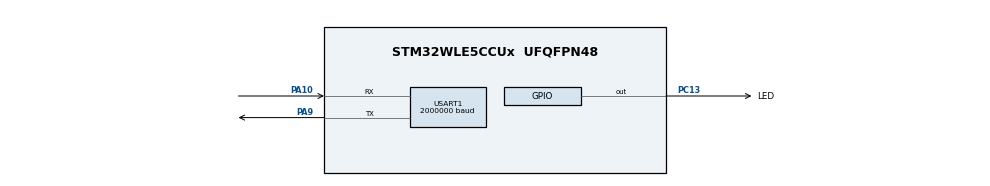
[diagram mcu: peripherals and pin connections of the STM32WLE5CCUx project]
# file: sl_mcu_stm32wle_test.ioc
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Mcu.Family=STM32WL
Mcu.Name=STM32WLE5CCUx
Mcu.Package=UFQFPN48
NVIC.PriorityGroup=NVIC_PRIORITYGROUP_4
OSC_IN.Mode=HSE-External-Oscillator
OSC_IN.Signal=RCC_OSC_IN
OSC_OUT.Mode=HSE-External-Oscillator
OSC_OUT.Signal=RCC_OSC_OUT
PA10.Mode=Asynchronous
PA10.Signal=USART1_RX
PA13.Mode=Trace_Asynchronous_SW
PA13.Signal=DEBUG_JTMS-SWDIO
PA14.Mode=Trace_Asynchronous_SW
PA14.Signal=DEBUG_JTCK-SWCLK
PA9.Mode=Asynchronous
PA9.Signal=USART1_TX
PB3.Mode=Trace_Asynchronous_SW
PB3.Signal=DEBUG_JTDO-SWO
PC13.GPIO_Label=LED
PC13.GPIO_ModeDefaultOutputPP=GPIO_MODE_OUTPUT_OD
PC13.GPIO_PuPd=GPIO_NOPULL
PC13.PinState=GPIO_PIN_SET
PC13.Signal=GPIO_Output
ProjectManager.HeapSize=0x200
ProjectManager.StackSize=0x400
ProjectManager.TargetToolchain=STM32CubeIDE
RCC.AHBFreq_Value=48000000
RCC.APB1Freq_Value=48000000
RCC.APB1TimFreq_Value=48000000
RCC.APB2Freq_Value=48000000
RCC.APB2TimFreq_Value=48000000
RCC.APB3Freq_Value=48000000
RCC.CortexFreq_Value=48000000
RCC.HCLKFreq_Value=48000000
RCC.HSEPRES=2
RCC.HSE_VALUE=32000000
RCC.HSI_VALUE=16000000
RCC.LSE_VALUE=32768
RCC.PLLN=6
RCC.PLLSourceVirtual=RCC_PLLSOURCE_HSE
RCC.SYSCLKFreq_VALUE=48000000
RCC.SYSCLKSource=RCC_SYSCLKSOURCE_PLLCLK
RCC.VCOOutputFreq_Value=96000000
USART1.BaudRate=2000000
USART1.VirtualMode-Asynchronous=VM_ASYNC
VP_ADV_TRACE_VS_ADV_TRACE.Mode=ADV_TRACE_Enabled
VP_MISC_VS_MISC.Mode=MISC_Enabled
VP_SEQUENCER_VS_SEQUENCER.Mode=SEQUENCER_Enabled
VP_SUBGHZ_PHY_VS_SubGhzPhy.Mode=SubGhzPhy_Enabled
VP_SUBGHZ_VS_SUBGHZ.Mode=SUBGHZ_Activate
VP_TIMER_VS_TIMER.Mode=TIMER_Enabled
VP_TINY_LPM_VS_TINY_LPM.Mode=TINY_LPM_Enabled
board=custom

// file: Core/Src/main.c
/* USER CODE BEGIN Header */
/**
 ******************************************************************************
 * @file           : main.c
 * @brief          : Main program body
 ******************************************************************************
 * @attention
 *
 * Copyright (c) 2026 STM32World <lth@stm32world.com>.
 * All rights reserved.
 *
 * This software is licensed under terms that can be found in the LICENSE file
 * in the root directory of this software component.
 * If no LICENSE file comes with this software, it is provided AS-IS.
 *
 ******************************************************************************
 */
/* USER CODE END Header */
#include "main.h"

/* USER CODE BEGIN Includes */
#include <stdio.h>
/* USER CODE END Includes */

UART_HandleTypeDef huart1;

void SystemClock_Config(void);
static void MX_GPIO_Init(void);
static void MX_USART1_UART_Init(void);

/* USER CODE BEGIN 0 */

// Send printf to uart1
int __io_putchar(int ch) {
    if (ch == '\n') {
        HAL_UART_Transmit(&huart1, (uint8_t*) "\r", 1, HAL_MAX_DELAY);
    }
    if (HAL_UART_Transmit(&huart1, (uint8_t*) &ch, 1, HAL_MAX_DELAY) != HAL_OK) {
        return -1;
    }
    return ch;
}

/* USER CODE END 0 */

int main(void)
{

    /* MCU Configuration--------------------------------------------------------*/

    /* Reset of all peripherals, Initializes the Flash interface and the Systick. */
    HAL_Init();

    /* Configure the system clock */
    SystemClock_Config();

    /* Initialize all configured peripherals */
    MX_GPIO_Init();
    MX_USART1_UART_Init();
    /* USER CODE BEGIN 2 */

    printf("\n\n\nStarting\n");

    /* USER CODE END 2 */

    /* Infinite loop */
    /* USER CODE BEGIN WHILE */

    uint32_t now = 0, next_blink = 500, next_tick = 1000;

    while (1) {

        now = uwTick;

        if (now >= next_blink) {
            HAL_GPIO_TogglePin(LED_GPIO_Port, LED_Pin);
            next_blink = now + 500;
        }

        if (now >= next_tick) {
            printf("Tick %lu\n", now / 1000);
            next_tick = now + 1000;
        }

        /* USER CODE END WHILE */

    }
}

void SystemClock_Config(void)
{
    RCC_OscInitTypeDef RCC_OscInitStruct = { 0 };
    RCC_ClkInitTypeDef RCC_ClkInitStruct = { 0 };

    /** Configure the main internal regulator output voltage
     */
    __HAL_PWR_VOLTAGESCALING_CONFIG(PWR_REGULATOR_VOLTAGE_SCALE1);

    /** Initializes the CPU, AHB and APB buses clocks
     */
    RCC_OscInitStruct.OscillatorType = RCC_OSCILLATORTYPE_HSE;
    RCC_OscInitStruct.HSEState = RCC_HSE_ON;
    RCC_OscInitStruct.HSEDiv = RCC_HSE_DIV2;
    RCC_OscInitStruct.PLL.PLLState = RCC_PLL_ON;
    RCC_OscInitStruct.PLL.PLLSource = RCC_PLLSOURCE_HSE;
    RCC_OscInitStruct.PLL.PLLM = RCC_PLLM_DIV1;
    RCC_OscInitStruct.PLL.PLLN = 6;
    RCC_OscInitStruct.PLL.PLLP = RCC_PLLP_DIV2;
    RCC_OscInitStruct.PLL.PLLR = RCC_PLLR_DIV2;
    RCC_OscInitStruct.PLL.PLLQ = RCC_PLLQ_DIV2;
    if (HAL_RCC_OscConfig(&RCC_OscInitStruct) != HAL_OK)
            {
        Error_Handler();
    }

    /** Enable the HSE Prescaler
     */
    __HAL_RCC_HSE_DIV2_ENABLE();

    /** Configure the SYSCLKSource, HCLK, PCLK1 and PCLK2 clocks dividers
     */
    RCC_ClkInitStruct.ClockType = RCC_CLOCKTYPE_HCLK3 | RCC_CLOCKTYPE_HCLK
            | RCC_CLOCKTYPE_SYSCLK | RCC_CLOCKTYPE_PCLK1
            | RCC_CLOCKTYPE_PCLK2;
    RCC_ClkInitStruct.SYSCLKSource = RCC_SYSCLKSOURCE_PLLCLK;
    RCC_ClkInitStruct.AHBCLKDivider = RCC_SYSCLK_DIV1;
    RCC_ClkInitStruct.APB1CLKDivider = RCC_HCLK_DIV1;
    RCC_ClkInitStruct.APB2CLKDivider = RCC_HCLK_DIV1;
    RCC_ClkInitStruct.AHBCLK3Divider = RCC_SYSCLK_DIV1;

    if (HAL_RCC_ClockConfig(&RCC_ClkInitStruct, FLASH_LATENCY_2) != HAL_OK)
            {
        Error_Handler();
    }
}

static void MX_USART1_UART_Init(void)
{

    huart1.Instance = USART1;
    huart1.Init.BaudRate = 2000000;
    huart1.Init.WordLength = UART_WORDLENGTH_8B;
    huart1.Init.StopBits = UART_STOPBITS_1;
    huart1.Init.Parity = UART_PARITY_NONE;
    huart1.Init.Mode = UART_MODE_TX_RX;
    huart1.Init.HwFlowCtl = UART_HWCONTROL_NONE;
    huart1.Init.OverSampling = UART_OVERSAMPLING_16;
    huart1.Init.OneBitSampling = UART_ONE_BIT_SAMPLE_DISABLE;
    huart1.Init.ClockPrescaler = UART_PRESCALER_DIV1;
    huart1.AdvancedInit.AdvFeatureInit = UART_ADVFEATURE_NO_INIT;
    if (HAL_UART_Init(&huart1) != HAL_OK)
            {
        Error_Handler();
    }
    if (HAL_UARTEx_SetTxFifoThreshold(&huart1, UART_TXFIFO_THRESHOLD_1_8) != HAL_OK)
            {
        Error_Handler();
    }
    if (HAL_UARTEx_SetRxFifoThreshold(&huart1, UART_RXFIFO_THRESHOLD_1_8) != HAL_OK)
            {
        Error_Handler();
    }
    if (HAL_UARTEx_DisableFifoMode(&huart1) != HAL_OK)
            {
        Error_Handler();
    }

}

static void MX_GPIO_Init(void)
{
    GPIO_InitTypeDef GPIO_InitStruct = { 0 };

    /* GPIO Ports Clock Enable */
    __HAL_RCC_GPIOB_CLK_ENABLE();
    __HAL_RCC_GPIOA_CLK_ENABLE();
    __HAL_RCC_GPIOC_CLK_ENABLE();

    /*Configure GPIO pin Output Level */
    HAL_GPIO_WritePin(LED_GPIO_Port, LED_Pin, GPIO_PIN_SET);

    /*Configure GPIO pin : LED_Pin */
    GPIO_InitStruct.Pin = LED_Pin;
    GPIO_InitStruct.Mode = GPIO_MODE_OUTPUT_OD;
    GPIO_InitStruct.Pull = GPIO_NOPULL;
    GPIO_InitStruct.Speed = GPIO_SPEED_FREQ_LOW;
    HAL_GPIO_Init(LED_GPIO_Port, &GPIO_InitStruct);

}

void Error_Handler(void)
{
    __disable_irq();
    while (1)
    {
    }
}
